VERSION 5.7 ;
  NOWIREEXTENSIONATPIN ON ;
  DIVIDERCHAR "/" ;
  BUSBITCHARS "[]" ;
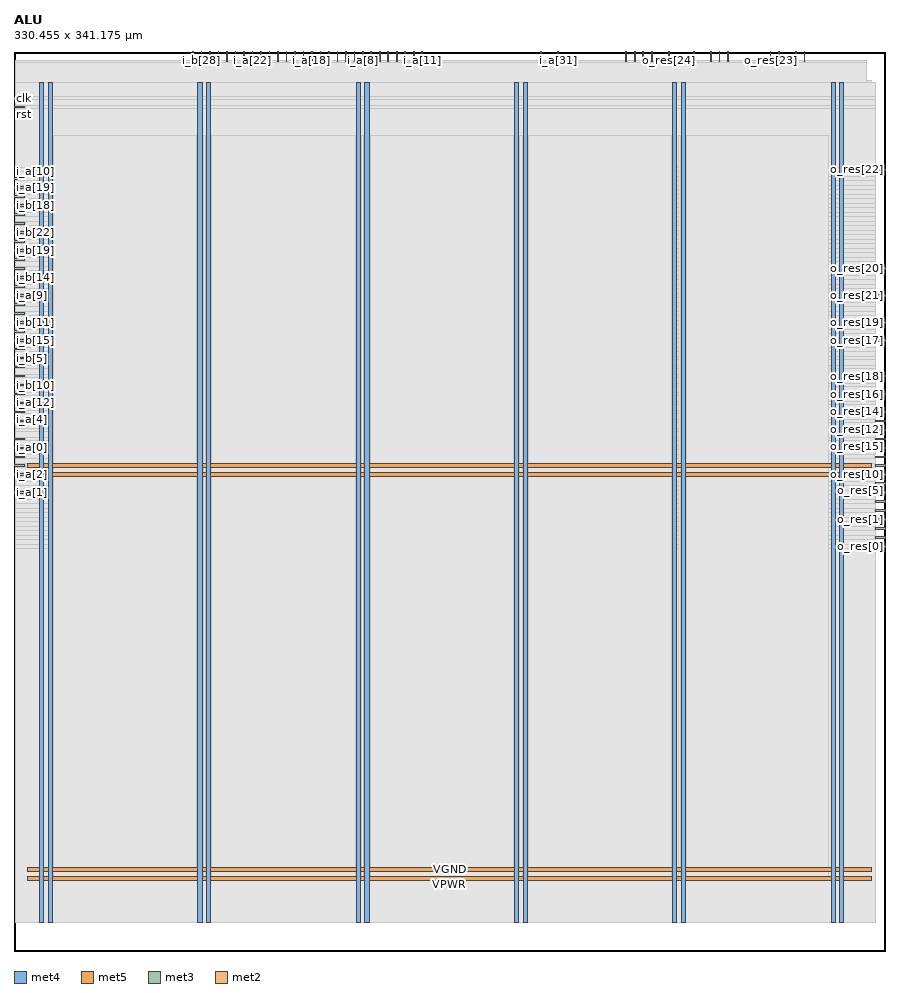
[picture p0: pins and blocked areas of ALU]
MACRO ALU
  CLASS BLOCK ;
  FOREIGN ALU ;
  ORIGIN 0.000 0.000 ;
  SIZE 330.455 BY 341.175 ;
  PIN VGND
    DIRECTION INOUT ;
    USE GROUND ;
    PORT
      LAYER met4 ;
        RECT 13.020 10.640 14.620 329.360 ;
    END
    PORT
      LAYER met4 ;
        RECT 73.020 10.640 74.620 329.360 ;
    END
    PORT
      LAYER met4 ;
        RECT 133.020 10.640 134.620 329.360 ;
    END
    PORT
      LAYER met4 ;
        RECT 193.020 10.640 194.620 329.360 ;
    END
    PORT
      LAYER met4 ;
        RECT 253.020 10.640 254.620 329.360 ;
    END
    PORT
      LAYER met4 ;
        RECT 313.020 10.640 314.620 329.360 ;
    END
    PORT
      LAYER met5 ;
        RECT 5.280 30.030 325.000 31.630 ;
    END
    PORT
      LAYER met5 ;
        RECT 5.280 183.210 325.000 184.810 ;
    END
  END VGND
  PIN VPWR
    DIRECTION INOUT ;
    USE POWER ;
    PORT
      LAYER met4 ;
        RECT 9.720 10.640 11.320 329.360 ;
    END
    PORT
      LAYER met4 ;
        RECT 69.720 10.640 71.320 329.360 ;
    END
    PORT
      LAYER met4 ;
        RECT 129.720 10.640 131.320 329.360 ;
    END
    PORT
      LAYER met4 ;
        RECT 189.720 10.640 191.320 329.360 ;
    END
    PORT
      LAYER met4 ;
        RECT 249.720 10.640 251.320 329.360 ;
    END
    PORT
      LAYER met4 ;
        RECT 309.720 10.640 311.320 329.360 ;
    END
    PORT
      LAYER met5 ;
        RECT 5.280 26.730 325.000 28.330 ;
    END
    PORT
      LAYER met5 ;
        RECT 5.280 179.910 325.000 181.510 ;
    END
  END VPWR
  PIN clk
    DIRECTION INPUT ;
    USE SIGNAL ;
    ANTENNAGATEAREA 0.852000 ;
    PORT
      LAYER met3 ;
        RECT 0.000 323.040 4.000 323.640 ;
    END
  END clk
  PIN i_a[0]
    DIRECTION INPUT ;
    USE SIGNAL ;
    ANTENNAGATEAREA 0.196500 ;
    PORT
      LAYER met3 ;
        RECT 0.000 190.440 4.000 191.040 ;
    END
  END i_a[0]
  PIN i_a[10]
    DIRECTION INPUT ;
    USE SIGNAL ;
    ANTENNAGATEAREA 0.196500 ;
    PORT
      LAYER met3 ;
        RECT 0.000 292.440 4.000 293.040 ;
    END
  END i_a[10]
  PIN i_a[11]
    DIRECTION INPUT ;
    USE SIGNAL ;
    ANTENNAGATEAREA 0.196500 ;
    PORT
      LAYER met2 ;
        RECT 154.650 337.175 154.930 341.175 ;
    END
  END i_a[11]
  PIN i_a[12]
    DIRECTION INPUT ;
    USE SIGNAL ;
    ANTENNAGATEAREA 0.196500 ;
    PORT
      LAYER met3 ;
        RECT 0.000 207.440 4.000 208.040 ;
    END
  END i_a[12]
  PIN i_a[13]
    DIRECTION INPUT ;
    USE SIGNAL ;
    ANTENNAGATEAREA 0.196500 ;
    PORT
      LAYER met2 ;
        RECT 122.450 337.175 122.730 341.175 ;
    END
  END i_a[13]
  PIN i_a[14]
    DIRECTION INPUT ;
    USE SIGNAL ;
    ANTENNAGATEAREA 0.196500 ;
    PORT
      LAYER met2 ;
        RECT 135.330 337.175 135.610 341.175 ;
    END
  END i_a[14]
  PIN i_a[15]
    DIRECTION INPUT ;
    USE SIGNAL ;
    ANTENNAGATEAREA 0.196500 ;
    PORT
      LAYER met3 ;
        RECT 0.000 251.640 4.000 252.240 ;
    END
  END i_a[15]
  PIN i_a[16]
    DIRECTION INPUT ;
    USE SIGNAL ;
    ANTENNAGATEAREA 0.196500 ;
    PORT
      LAYER met3 ;
        RECT 0.000 261.840 4.000 262.440 ;
    END
  END i_a[16]
  PIN i_a[17]
    DIRECTION INPUT ;
    USE SIGNAL ;
    ANTENNAGATEAREA 0.196500 ;
    PORT
      LAYER met2 ;
        RECT 144.990 337.175 145.270 341.175 ;
    END
  END i_a[17]
  PIN i_a[18]
    DIRECTION INPUT ;
    USE SIGNAL ;
    ANTENNAGATEAREA 0.196500 ;
    PORT
      LAYER met2 ;
        RECT 112.790 337.175 113.070 341.175 ;
    END
  END i_a[18]
  PIN i_a[19]
    DIRECTION INPUT ;
    USE SIGNAL ;
    ANTENNAGATEAREA 0.196500 ;
    PORT
      LAYER met3 ;
        RECT 0.000 289.040 4.000 289.640 ;
    END
  END i_a[19]
  PIN i_a[1]
    DIRECTION INPUT ;
    USE SIGNAL ;
    ANTENNAGATEAREA 0.196500 ;
    PORT
      LAYER met3 ;
        RECT 0.000 173.440 4.000 174.040 ;
    END
  END i_a[1]
  PIN i_a[20]
    DIRECTION INPUT ;
    USE SIGNAL ;
    ANTENNAGATEAREA 0.196500 ;
    PORT
      LAYER met3 ;
        RECT 0.000 285.640 4.000 286.240 ;
    END
  END i_a[20]
  PIN i_a[21]
    DIRECTION INPUT ;
    USE SIGNAL ;
    ANTENNAGATEAREA 0.196500 ;
    PORT
      LAYER met2 ;
        RECT 67.710 337.175 67.990 341.175 ;
    END
  END i_a[21]
  PIN i_a[22]
    DIRECTION INPUT ;
    USE SIGNAL ;
    ANTENNAGATEAREA 0.196500 ;
    PORT
      LAYER met2 ;
        RECT 90.250 337.175 90.530 341.175 ;
    END
  END i_a[22]
  PIN i_a[23]
    DIRECTION INPUT ;
    USE SIGNAL ;
    ANTENNAGATEAREA 0.196500 ;
    PORT
      LAYER met2 ;
        RECT 138.550 337.175 138.830 341.175 ;
    END
  END i_a[23]
  PIN i_a[24]
    DIRECTION INPUT ;
    USE SIGNAL ;
    ANTENNAGATEAREA 0.196500 ;
    PORT
      LAYER met2 ;
        RECT 141.770 337.175 142.050 341.175 ;
    END
  END i_a[24]
  PIN i_a[25]
    DIRECTION INPUT ;
    USE SIGNAL ;
    ANTENNAGATEAREA 0.196500 ;
    PORT
      LAYER met2 ;
        RECT 128.890 337.175 129.170 341.175 ;
    END
  END i_a[25]
  PIN i_a[26]
    DIRECTION INPUT ;
    USE SIGNAL ;
    ANTENNAGATEAREA 0.196500 ;
    PORT
      LAYER met2 ;
        RECT 125.670 337.175 125.950 341.175 ;
    END
  END i_a[26]
  PIN i_a[27]
    DIRECTION INPUT ;
    USE SIGNAL ;
    ANTENNAGATEAREA 0.196500 ;
    PORT
      LAYER met2 ;
        RECT 119.230 337.175 119.510 341.175 ;
    END
  END i_a[27]
  PIN i_a[28]
    DIRECTION INPUT ;
    USE SIGNAL ;
    ANTENNAGATEAREA 0.196500 ;
    PORT
      LAYER met2 ;
        RECT 116.010 337.175 116.290 341.175 ;
    END
  END i_a[28]
  PIN i_a[29]
    DIRECTION INPUT ;
    USE SIGNAL ;
    ANTENNAGATEAREA 0.196500 ;
    PORT
      LAYER met2 ;
        RECT 151.430 337.175 151.710 341.175 ;
    END
  END i_a[29]
  PIN i_a[2]
    DIRECTION INPUT ;
    USE SIGNAL ;
    ANTENNAGATEAREA 0.196500 ;
    PORT
      LAYER met3 ;
        RECT 0.000 180.240 4.000 180.840 ;
    END
  END i_a[2]
  PIN i_a[30]
    DIRECTION INPUT ;
    USE SIGNAL ;
    ANTENNAGATEAREA 0.196500 ;
    PORT
      LAYER met2 ;
        RECT 109.570 337.175 109.850 341.175 ;
    END
  END i_a[30]
  PIN i_a[31]
    DIRECTION INPUT ;
    USE SIGNAL ;
    ANTENNAGATEAREA 0.196500 ;
    PORT
      LAYER met2 ;
        RECT 206.170 337.175 206.450 341.175 ;
    END
  END i_a[31]
  PIN i_a[3]
    DIRECTION INPUT ;
    USE SIGNAL ;
    ANTENNAGATEAREA 0.196500 ;
    PORT
      LAYER met3 ;
        RECT 0.000 183.640 4.000 184.240 ;
    END
  END i_a[3]
  PIN i_a[4]
    DIRECTION INPUT ;
    USE SIGNAL ;
    ANTENNAGATEAREA 0.196500 ;
    PORT
      LAYER met3 ;
        RECT 0.000 204.040 4.000 204.640 ;
    END
  END i_a[4]
  PIN i_a[5]
    DIRECTION INPUT ;
    USE SIGNAL ;
    ANTENNAGATEAREA 0.196500 ;
    PORT
      LAYER met3 ;
        RECT 0.000 193.840 4.000 194.440 ;
    END
  END i_a[5]
  PIN i_a[6]
    DIRECTION INPUT ;
    USE SIGNAL ;
    ANTENNAGATEAREA 0.196500 ;
    PORT
      LAYER met3 ;
        RECT 0.000 187.040 4.000 187.640 ;
    END
  END i_a[6]
  PIN i_a[7]
    DIRECTION INPUT ;
    USE SIGNAL ;
    ANTENNAGATEAREA 0.196500 ;
    PORT
      LAYER met3 ;
        RECT 0.000 200.640 4.000 201.240 ;
    END
  END i_a[7]
  PIN i_a[8]
    DIRECTION INPUT ;
    USE SIGNAL ;
    ANTENNAGATEAREA 0.196500 ;
    PORT
      LAYER met2 ;
        RECT 132.110 337.175 132.390 341.175 ;
    END
  END i_a[8]
  PIN i_a[9]
    DIRECTION INPUT ;
    USE SIGNAL ;
    ANTENNAGATEAREA 0.196500 ;
    PORT
      LAYER met3 ;
        RECT 0.000 248.240 4.000 248.840 ;
    END
  END i_a[9]
  PIN i_b[0]
    DIRECTION INPUT ;
    USE SIGNAL ;
    ANTENNAGATEAREA 0.196500 ;
    PORT
      LAYER met2 ;
        RECT 103.130 337.175 103.410 341.175 ;
    END
  END i_b[0]
  PIN i_b[10]
    DIRECTION INPUT ;
    USE SIGNAL ;
    ANTENNAGATEAREA 0.196500 ;
    PORT
      LAYER met3 ;
        RECT 0.000 214.240 4.000 214.840 ;
    END
  END i_b[10]
  PIN i_b[11]
    DIRECTION INPUT ;
    USE SIGNAL ;
    ANTENNAGATEAREA 0.196500 ;
    PORT
      LAYER met3 ;
        RECT 0.000 238.040 4.000 238.640 ;
    END
  END i_b[11]
  PIN i_b[12]
    DIRECTION INPUT ;
    USE SIGNAL ;
    ANTENNAGATEAREA 0.196500 ;
    PORT
      LAYER met3 ;
        RECT 0.000 217.640 4.000 218.240 ;
    END
  END i_b[12]
  PIN i_b[13]
    DIRECTION INPUT ;
    USE SIGNAL ;
    ANTENNAGATEAREA 0.196500 ;
    PORT
      LAYER met3 ;
        RECT 0.000 244.840 4.000 245.440 ;
    END
  END i_b[13]
  PIN i_b[14]
    DIRECTION INPUT ;
    USE SIGNAL ;
    ANTENNAGATEAREA 0.196500 ;
    PORT
      LAYER met3 ;
        RECT 0.000 255.040 4.000 255.640 ;
    END
  END i_b[14]
  PIN i_b[15]
    DIRECTION INPUT ;
    USE SIGNAL ;
    ANTENNAGATEAREA 0.196500 ;
    PORT
      LAYER met3 ;
        RECT 0.000 231.240 4.000 231.840 ;
    END
  END i_b[15]
  PIN i_b[16]
    DIRECTION INPUT ;
    USE SIGNAL ;
    ANTENNAGATEAREA 0.196500 ;
    PORT
      LAYER met3 ;
        RECT 0.000 258.440 4.000 259.040 ;
    END
  END i_b[16]
  PIN i_b[17]
    DIRECTION INPUT ;
    USE SIGNAL ;
    ANTENNAGATEAREA 0.196500 ;
    PORT
      LAYER met3 ;
        RECT 0.000 268.640 4.000 269.240 ;
    END
  END i_b[17]
  PIN i_b[18]
    DIRECTION INPUT ;
    USE SIGNAL ;
    ANTENNAGATEAREA 0.196500 ;
    PORT
      LAYER met3 ;
        RECT 0.000 282.240 4.000 282.840 ;
    END
  END i_b[18]
  PIN i_b[19]
    DIRECTION INPUT ;
    USE SIGNAL ;
    ANTENNAGATEAREA 0.196500 ;
    PORT
      LAYER met3 ;
        RECT 0.000 265.240 4.000 265.840 ;
    END
  END i_b[19]
  PIN i_b[1]
    DIRECTION INPUT ;
    USE SIGNAL ;
    ANTENNAGATEAREA 0.196500 ;
    PORT
      LAYER met2 ;
        RECT 148.210 337.175 148.490 341.175 ;
    END
  END i_b[1]
  PIN i_b[20]
    DIRECTION INPUT ;
    USE SIGNAL ;
    ANTENNAGATEAREA 0.196500 ;
    PORT
      LAYER met3 ;
        RECT 0.000 278.840 4.000 279.440 ;
    END
  END i_b[20]
  PIN i_b[21]
    DIRECTION INPUT ;
    USE SIGNAL ;
    ANTENNAGATEAREA 0.196500 ;
    PORT
      LAYER met3 ;
        RECT 0.000 275.440 4.000 276.040 ;
    END
  END i_b[21]
  PIN i_b[22]
    DIRECTION INPUT ;
    USE SIGNAL ;
    ANTENNAGATEAREA 0.196500 ;
    PORT
      LAYER met3 ;
        RECT 0.000 272.040 4.000 272.640 ;
    END
  END i_b[22]
  PIN i_b[23]
    DIRECTION INPUT ;
    USE SIGNAL ;
    ANTENNAGATEAREA 0.196500 ;
    PORT
      LAYER met2 ;
        RECT 74.150 337.175 74.430 341.175 ;
    END
  END i_b[23]
  PIN i_b[24]
    DIRECTION INPUT ;
    USE SIGNAL ;
    ANTENNAGATEAREA 0.196500 ;
    PORT
      LAYER met2 ;
        RECT 77.370 337.175 77.650 341.175 ;
    END
  END i_b[24]
  PIN i_b[25]
    DIRECTION INPUT ;
    USE SIGNAL ;
    ANTENNAGATEAREA 0.196500 ;
    PORT
      LAYER met2 ;
        RECT 93.470 337.175 93.750 341.175 ;
    END
  END i_b[25]
  PIN i_b[26]
    DIRECTION INPUT ;
    USE SIGNAL ;
    ANTENNAGATEAREA 0.196500 ;
    PORT
      LAYER met2 ;
        RECT 96.690 337.175 96.970 341.175 ;
    END
  END i_b[26]
  PIN i_b[27]
    DIRECTION INPUT ;
    USE SIGNAL ;
    ANTENNAGATEAREA 0.196500 ;
    PORT
      LAYER met2 ;
        RECT 87.030 337.175 87.310 341.175 ;
    END
  END i_b[27]
  PIN i_b[28]
    DIRECTION INPUT ;
    USE SIGNAL ;
    ANTENNAGATEAREA 0.196500 ;
    PORT
      LAYER met2 ;
        RECT 70.930 337.175 71.210 341.175 ;
    END
  END i_b[28]
  PIN i_b[29]
    DIRECTION INPUT ;
    USE SIGNAL ;
    ANTENNAGATEAREA 0.196500 ;
    PORT
      LAYER met2 ;
        RECT 80.590 337.175 80.870 341.175 ;
    END
  END i_b[29]
  PIN i_b[2]
    DIRECTION INPUT ;
    USE SIGNAL ;
    ANTENNAGATEAREA 0.196500 ;
    PORT
      LAYER met2 ;
        RECT 106.350 337.175 106.630 341.175 ;
    END
  END i_b[2]
  PIN i_b[30]
    DIRECTION INPUT ;
    USE SIGNAL ;
    ANTENNAGATEAREA 0.196500 ;
    PORT
      LAYER met2 ;
        RECT 83.810 337.175 84.090 341.175 ;
    END
  END i_b[30]
  PIN i_b[31]
    DIRECTION INPUT ;
    USE SIGNAL ;
    ANTENNAGATEAREA 0.196500 ;
    PORT
      LAYER met2 ;
        RECT 199.730 337.175 200.010 341.175 ;
    END
  END i_b[31]
  PIN i_b[3]
    DIRECTION INPUT ;
    USE SIGNAL ;
    ANTENNAGATEAREA 0.196500 ;
    PORT
      LAYER met2 ;
        RECT 99.910 337.175 100.190 341.175 ;
    END
  END i_b[3]
  PIN i_b[4]
    DIRECTION INPUT ;
    USE SIGNAL ;
    ANTENNAGATEAREA 0.196500 ;
    PORT
      LAYER met3 ;
        RECT 0.000 234.640 4.000 235.240 ;
    END
  END i_b[4]
  PIN i_b[5]
    DIRECTION INPUT ;
    USE SIGNAL ;
    ANTENNAGATEAREA 0.196500 ;
    PORT
      LAYER met3 ;
        RECT 0.000 224.440 4.000 225.040 ;
    END
  END i_b[5]
  PIN i_b[6]
    DIRECTION INPUT ;
    USE SIGNAL ;
    ANTENNAGATEAREA 0.196500 ;
    PORT
      LAYER met3 ;
        RECT 0.000 221.040 4.000 221.640 ;
    END
  END i_b[6]
  PIN i_b[7]
    DIRECTION INPUT ;
    USE SIGNAL ;
    ANTENNAGATEAREA 0.196500 ;
    PORT
      LAYER met3 ;
        RECT 0.000 227.840 4.000 228.440 ;
    END
  END i_b[7]
  PIN i_b[8]
    DIRECTION INPUT ;
    USE SIGNAL ;
    ANTENNAGATEAREA 0.196500 ;
    PORT
      LAYER met3 ;
        RECT 0.000 241.440 4.000 242.040 ;
    END
  END i_b[8]
  PIN i_b[9]
    DIRECTION INPUT ;
    USE SIGNAL ;
    ANTENNAGATEAREA 0.196500 ;
    PORT
      LAYER met3 ;
        RECT 0.000 210.840 4.000 211.440 ;
    END
  END i_b[9]
  PIN i_vld
    DIRECTION INPUT ;
    USE SIGNAL ;
    ANTENNAGATEAREA 0.196500 ;
    PORT
      LAYER met2 ;
        RECT 264.130 337.175 264.410 341.175 ;
    END
  END i_vld
  PIN o_res[0]
    DIRECTION OUTPUT ;
    USE SIGNAL ;
    ANTENNADIFFAREA 0.445500 ;
    PORT
      LAYER met3 ;
        RECT 326.455 153.040 330.455 153.640 ;
    END
  END o_res[0]
  PIN o_res[10]
    DIRECTION OUTPUT ;
    USE SIGNAL ;
    ANTENNADIFFAREA 0.445500 ;
    PORT
      LAYER met3 ;
        RECT 326.455 180.240 330.455 180.840 ;
    END
  END o_res[10]
  PIN o_res[11]
    DIRECTION OUTPUT ;
    USE SIGNAL ;
    ANTENNADIFFAREA 0.445500 ;
    PORT
      LAYER met3 ;
        RECT 326.455 200.640 330.455 201.240 ;
    END
  END o_res[11]
  PIN o_res[12]
    DIRECTION OUTPUT ;
    USE SIGNAL ;
    ANTENNADIFFAREA 0.445500 ;
    PORT
      LAYER met3 ;
        RECT 326.455 197.240 330.455 197.840 ;
    END
  END o_res[12]
  PIN o_res[13]
    DIRECTION OUTPUT ;
    USE SIGNAL ;
    ANTENNADIFFAREA 0.445500 ;
    PORT
      LAYER met3 ;
        RECT 326.455 183.640 330.455 184.240 ;
    END
  END o_res[13]
  PIN o_res[14]
    DIRECTION OUTPUT ;
    USE SIGNAL ;
    ANTENNADIFFAREA 0.445500 ;
    PORT
      LAYER met3 ;
        RECT 326.455 204.040 330.455 204.640 ;
    END
  END o_res[14]
  PIN o_res[15]
    DIRECTION OUTPUT ;
    USE SIGNAL ;
    ANTENNADIFFAREA 0.445500 ;
    PORT
      LAYER met3 ;
        RECT 326.455 193.840 330.455 194.440 ;
    END
  END o_res[15]
  PIN o_res[16]
    DIRECTION OUTPUT ;
    USE SIGNAL ;
    ANTENNADIFFAREA 0.445500 ;
    PORT
      LAYER met3 ;
        RECT 326.455 210.840 330.455 211.440 ;
    END
  END o_res[16]
  PIN o_res[17]
    DIRECTION OUTPUT ;
    USE SIGNAL ;
    ANTENNADIFFAREA 0.445500 ;
    PORT
      LAYER met3 ;
        RECT 326.455 231.240 330.455 231.840 ;
    END
  END o_res[17]
  PIN o_res[18]
    DIRECTION OUTPUT ;
    USE SIGNAL ;
    ANTENNADIFFAREA 0.445500 ;
    PORT
      LAYER met3 ;
        RECT 326.455 217.640 330.455 218.240 ;
    END
  END o_res[18]
  PIN o_res[19]
    DIRECTION OUTPUT ;
    USE SIGNAL ;
    ANTENNADIFFAREA 0.445500 ;
    PORT
      LAYER met3 ;
        RECT 326.455 238.040 330.455 238.640 ;
    END
  END o_res[19]
  PIN o_res[1]
    DIRECTION OUTPUT ;
    USE SIGNAL ;
    ANTENNADIFFAREA 0.445500 ;
    PORT
      LAYER met3 ;
        RECT 326.455 163.240 330.455 163.840 ;
    END
  END o_res[1]
  PIN o_res[20]
    DIRECTION OUTPUT ;
    USE SIGNAL ;
    ANTENNADIFFAREA 0.445500 ;
    PORT
      LAYER met3 ;
        RECT 326.455 258.440 330.455 259.040 ;
    END
  END o_res[20]
  PIN o_res[21]
    DIRECTION OUTPUT ;
    USE SIGNAL ;
    ANTENNADIFFAREA 0.445500 ;
    PORT
      LAYER met3 ;
        RECT 326.455 248.240 330.455 248.840 ;
    END
  END o_res[21]
  PIN o_res[22]
    DIRECTION OUTPUT ;
    USE SIGNAL ;
    ANTENNADIFFAREA 0.445500 ;
    PORT
      LAYER met3 ;
        RECT 326.455 295.840 330.455 296.440 ;
    END
  END o_res[22]
  PIN o_res[23]
    DIRECTION OUTPUT ;
    USE SIGNAL ;
    ANTENNADIFFAREA 0.445500 ;
    PORT
      LAYER met2 ;
        RECT 286.670 337.175 286.950 341.175 ;
    END
  END o_res[23]
  PIN o_res[24]
    DIRECTION OUTPUT ;
    USE SIGNAL ;
    ANTENNADIFFAREA 0.445500 ;
    PORT
      LAYER met2 ;
        RECT 248.030 337.175 248.310 341.175 ;
    END
  END o_res[24]
  PIN o_res[25]
    DIRECTION OUTPUT ;
    USE SIGNAL ;
    ANTENNADIFFAREA 0.445500 ;
    PORT
      LAYER met2 ;
        RECT 270.570 337.175 270.850 341.175 ;
    END
  END o_res[25]
  PIN o_res[26]
    DIRECTION OUTPUT ;
    USE SIGNAL ;
    ANTENNADIFFAREA 0.445500 ;
    PORT
      LAYER met2 ;
        RECT 257.690 337.175 257.970 341.175 ;
    END
  END o_res[26]
  PIN o_res[27]
    DIRECTION OUTPUT ;
    USE SIGNAL ;
    ANTENNADIFFAREA 0.445500 ;
    PORT
      LAYER met2 ;
        RECT 289.890 337.175 290.170 341.175 ;
    END
  END o_res[27]
  PIN o_res[28]
    DIRECTION OUTPUT ;
    USE SIGNAL ;
    ANTENNADIFFAREA 0.445500 ;
    PORT
      LAYER met2 ;
        RECT 296.330 337.175 296.610 341.175 ;
    END
  END o_res[28]
  PIN o_res[29]
    DIRECTION OUTPUT ;
    USE SIGNAL ;
    ANTENNADIFFAREA 0.445500 ;
    PORT
      LAYER met2 ;
        RECT 241.590 337.175 241.870 341.175 ;
    END
  END o_res[29]
  PIN o_res[2]
    DIRECTION OUTPUT ;
    USE SIGNAL ;
    ANTENNADIFFAREA 0.445500 ;
    PORT
      LAYER met3 ;
        RECT 326.455 156.440 330.455 157.040 ;
    END
  END o_res[2]
  PIN o_res[30]
    DIRECTION OUTPUT ;
    USE SIGNAL ;
    ANTENNADIFFAREA 0.445500 ;
    PORT
      LAYER met2 ;
        RECT 267.350 337.175 267.630 341.175 ;
    END
  END o_res[30]
  PIN o_res[31]
    DIRECTION OUTPUT ;
    USE SIGNAL ;
    ANTENNADIFFAREA 0.445500 ;
    PORT
      LAYER met2 ;
        RECT 238.370 337.175 238.650 341.175 ;
    END
  END o_res[31]
  PIN o_res[3]
    DIRECTION OUTPUT ;
    USE SIGNAL ;
    ANTENNADIFFAREA 0.445500 ;
    PORT
      LAYER met3 ;
        RECT 326.455 166.640 330.455 167.240 ;
    END
  END o_res[3]
  PIN o_res[4]
    DIRECTION OUTPUT ;
    USE SIGNAL ;
    ANTENNADIFFAREA 0.445500 ;
    PORT
      LAYER met3 ;
        RECT 326.455 187.040 330.455 187.640 ;
    END
  END o_res[4]
  PIN o_res[5]
    DIRECTION OUTPUT ;
    USE SIGNAL ;
    ANTENNADIFFAREA 0.445500 ;
    PORT
      LAYER met3 ;
        RECT 326.455 176.840 330.455 177.440 ;
    END
  END o_res[5]
  PIN o_res[6]
    DIRECTION OUTPUT ;
    USE SIGNAL ;
    ANTENNADIFFAREA 0.445500 ;
    PORT
      LAYER met3 ;
        RECT 326.455 190.440 330.455 191.040 ;
    END
  END o_res[6]
  PIN o_res[7]
    DIRECTION OUTPUT ;
    USE SIGNAL ;
    ANTENNADIFFAREA 0.445500 ;
    PORT
      LAYER met3 ;
        RECT 326.455 173.440 330.455 174.040 ;
    END
  END o_res[7]
  PIN o_res[8]
    DIRECTION OUTPUT ;
    USE SIGNAL ;
    ANTENNADIFFAREA 0.445500 ;
    PORT
      LAYER met3 ;
        RECT 326.455 170.040 330.455 170.640 ;
    END
  END o_res[8]
  PIN o_res[9]
    DIRECTION OUTPUT ;
    USE SIGNAL ;
    ANTENNADIFFAREA 0.445500 ;
    PORT
      LAYER met3 ;
        RECT 326.455 159.840 330.455 160.440 ;
    END
  END o_res[9]
  PIN o_res_vld
    DIRECTION OUTPUT ;
    USE SIGNAL ;
    ANTENNADIFFAREA 0.445500 ;
    PORT
      LAYER met2 ;
        RECT 231.930 337.175 232.210 341.175 ;
    END
  END o_res_vld
  PIN opcode
    DIRECTION INPUT ;
    USE SIGNAL ;
    ANTENNAGATEAREA 0.196500 ;
    PORT
      LAYER met2 ;
        RECT 299.550 337.175 299.830 341.175 ;
    END
  END opcode
  PIN overflow
    DIRECTION OUTPUT ;
    USE SIGNAL ;
    ANTENNADIFFAREA 0.445500 ;
    PORT
      LAYER met2 ;
        RECT 235.150 337.175 235.430 341.175 ;
    END
  END overflow
  PIN rst
    DIRECTION INPUT ;
    USE SIGNAL ;
    ANTENNAGATEAREA 0.213000 ;
    PORT
      LAYER met3 ;
        RECT 0.000 319.640 4.000 320.240 ;
    END
  END rst
  OBS
      LAYER nwell ;
        RECT 5.330 10.795 324.950 329.310 ;
      LAYER li1 ;
        RECT 5.520 10.795 324.760 329.205 ;
      LAYER met1 ;
        RECT 4.210 10.640 325.060 330.100 ;
      LAYER met2 ;
        RECT 0.550 336.895 67.430 337.690 ;
        RECT 68.270 336.895 70.650 337.690 ;
        RECT 71.490 336.895 73.870 337.690 ;
        RECT 74.710 336.895 77.090 337.690 ;
        RECT 77.930 336.895 80.310 337.690 ;
        RECT 81.150 336.895 83.530 337.690 ;
        RECT 84.370 336.895 86.750 337.690 ;
        RECT 87.590 336.895 89.970 337.690 ;
        RECT 90.810 336.895 93.190 337.690 ;
        RECT 94.030 336.895 96.410 337.690 ;
        RECT 97.250 336.895 99.630 337.690 ;
        RECT 100.470 336.895 102.850 337.690 ;
        RECT 103.690 336.895 106.070 337.690 ;
        RECT 106.910 336.895 109.290 337.690 ;
        RECT 110.130 336.895 112.510 337.690 ;
        RECT 113.350 336.895 115.730 337.690 ;
        RECT 116.570 336.895 118.950 337.690 ;
        RECT 119.790 336.895 122.170 337.690 ;
        RECT 123.010 336.895 125.390 337.690 ;
        RECT 126.230 336.895 128.610 337.690 ;
        RECT 129.450 336.895 131.830 337.690 ;
        RECT 132.670 336.895 135.050 337.690 ;
        RECT 135.890 336.895 138.270 337.690 ;
        RECT 139.110 336.895 141.490 337.690 ;
        RECT 142.330 336.895 144.710 337.690 ;
        RECT 145.550 336.895 147.930 337.690 ;
        RECT 148.770 336.895 151.150 337.690 ;
        RECT 151.990 336.895 154.370 337.690 ;
        RECT 155.210 336.895 199.450 337.690 ;
        RECT 200.290 336.895 205.890 337.690 ;
        RECT 206.730 336.895 231.650 337.690 ;
        RECT 232.490 336.895 234.870 337.690 ;
        RECT 235.710 336.895 238.090 337.690 ;
        RECT 238.930 336.895 241.310 337.690 ;
        RECT 242.150 336.895 247.750 337.690 ;
        RECT 248.590 336.895 257.410 337.690 ;
        RECT 258.250 336.895 263.850 337.690 ;
        RECT 264.690 336.895 267.070 337.690 ;
        RECT 267.910 336.895 270.290 337.690 ;
        RECT 271.130 336.895 286.390 337.690 ;
        RECT 287.230 336.895 289.610 337.690 ;
        RECT 290.450 336.895 296.050 337.690 ;
        RECT 296.890 336.895 299.270 337.690 ;
        RECT 300.110 336.895 323.290 337.690 ;
        RECT 0.550 10.695 323.290 336.895 ;
      LAYER met3 ;
        RECT 0.525 324.040 326.455 329.285 ;
        RECT 4.400 322.640 326.455 324.040 ;
        RECT 0.525 320.640 326.455 322.640 ;
        RECT 4.400 319.240 326.455 320.640 ;
        RECT 0.525 296.840 326.455 319.240 ;
        RECT 0.525 295.440 326.055 296.840 ;
        RECT 0.525 293.440 326.455 295.440 ;
        RECT 4.400 292.040 326.455 293.440 ;
        RECT 0.525 290.040 326.455 292.040 ;
        RECT 4.400 288.640 326.455 290.040 ;
        RECT 0.525 286.640 326.455 288.640 ;
        RECT 4.400 285.240 326.455 286.640 ;
        RECT 0.525 283.240 326.455 285.240 ;
        RECT 4.400 281.840 326.455 283.240 ;
        RECT 0.525 279.840 326.455 281.840 ;
        RECT 4.400 278.440 326.455 279.840 ;
        RECT 0.525 276.440 326.455 278.440 ;
        RECT 4.400 275.040 326.455 276.440 ;
        RECT 0.525 273.040 326.455 275.040 ;
        RECT 4.400 271.640 326.455 273.040 ;
        RECT 0.525 269.640 326.455 271.640 ;
        RECT 4.400 268.240 326.455 269.640 ;
        RECT 0.525 266.240 326.455 268.240 ;
        RECT 4.400 264.840 326.455 266.240 ;
        RECT 0.525 262.840 326.455 264.840 ;
        RECT 4.400 261.440 326.455 262.840 ;
        RECT 0.525 259.440 326.455 261.440 ;
        RECT 4.400 258.040 326.055 259.440 ;
        RECT 0.525 256.040 326.455 258.040 ;
        RECT 4.400 254.640 326.455 256.040 ;
        RECT 0.525 252.640 326.455 254.640 ;
        RECT 4.400 251.240 326.455 252.640 ;
        RECT 0.525 249.240 326.455 251.240 ;
        RECT 4.400 247.840 326.055 249.240 ;
        RECT 0.525 245.840 326.455 247.840 ;
        RECT 4.400 244.440 326.455 245.840 ;
        RECT 0.525 242.440 326.455 244.440 ;
        RECT 4.400 241.040 326.455 242.440 ;
        RECT 0.525 239.040 326.455 241.040 ;
        RECT 4.400 237.640 326.055 239.040 ;
        RECT 0.525 235.640 326.455 237.640 ;
        RECT 4.400 234.240 326.455 235.640 ;
        RECT 0.525 232.240 326.455 234.240 ;
        RECT 4.400 230.840 326.055 232.240 ;
        RECT 0.525 228.840 326.455 230.840 ;
        RECT 4.400 227.440 326.455 228.840 ;
        RECT 0.525 225.440 326.455 227.440 ;
        RECT 4.400 224.040 326.455 225.440 ;
        RECT 0.525 222.040 326.455 224.040 ;
        RECT 4.400 220.640 326.455 222.040 ;
        RECT 0.525 218.640 326.455 220.640 ;
        RECT 4.400 217.240 326.055 218.640 ;
        RECT 0.525 215.240 326.455 217.240 ;
        RECT 4.400 213.840 326.455 215.240 ;
        RECT 0.525 211.840 326.455 213.840 ;
        RECT 4.400 210.440 326.055 211.840 ;
        RECT 0.525 208.440 326.455 210.440 ;
        RECT 4.400 207.040 326.455 208.440 ;
        RECT 0.525 205.040 326.455 207.040 ;
        RECT 4.400 203.640 326.055 205.040 ;
        RECT 0.525 201.640 326.455 203.640 ;
        RECT 4.400 200.240 326.055 201.640 ;
        RECT 0.525 198.240 326.455 200.240 ;
        RECT 0.525 196.840 326.055 198.240 ;
        RECT 0.525 194.840 326.455 196.840 ;
        RECT 4.400 193.440 326.055 194.840 ;
        RECT 0.525 191.440 326.455 193.440 ;
        RECT 4.400 190.040 326.055 191.440 ;
        RECT 0.525 188.040 326.455 190.040 ;
        RECT 4.400 186.640 326.055 188.040 ;
        RECT 0.525 184.640 326.455 186.640 ;
        RECT 4.400 183.240 326.055 184.640 ;
        RECT 0.525 181.240 326.455 183.240 ;
        RECT 4.400 179.840 326.055 181.240 ;
        RECT 0.525 177.840 326.455 179.840 ;
        RECT 0.525 176.440 326.055 177.840 ;
        RECT 0.525 174.440 326.455 176.440 ;
        RECT 4.400 173.040 326.055 174.440 ;
        RECT 0.525 171.040 326.455 173.040 ;
        RECT 0.525 169.640 326.055 171.040 ;
        RECT 0.525 167.640 326.455 169.640 ;
        RECT 0.525 166.240 326.055 167.640 ;
        RECT 0.525 164.240 326.455 166.240 ;
        RECT 0.525 162.840 326.055 164.240 ;
        RECT 0.525 160.840 326.455 162.840 ;
        RECT 0.525 159.440 326.055 160.840 ;
        RECT 0.525 157.440 326.455 159.440 ;
        RECT 0.525 156.040 326.055 157.440 ;
        RECT 0.525 154.040 326.455 156.040 ;
        RECT 0.525 152.640 326.055 154.040 ;
        RECT 0.525 10.715 326.455 152.640 ;
      LAYER met4 ;
        RECT 15.020 28.055 69.320 309.225 ;
        RECT 71.720 28.055 72.620 309.225 ;
        RECT 75.020 28.055 129.320 309.225 ;
        RECT 131.720 28.055 132.620 309.225 ;
        RECT 135.020 28.055 189.320 309.225 ;
        RECT 191.720 28.055 192.620 309.225 ;
        RECT 195.020 28.055 249.320 309.225 ;
        RECT 251.720 28.055 252.620 309.225 ;
        RECT 255.020 28.055 308.825 309.225 ;
  END
END ALU
END LIBRARY

